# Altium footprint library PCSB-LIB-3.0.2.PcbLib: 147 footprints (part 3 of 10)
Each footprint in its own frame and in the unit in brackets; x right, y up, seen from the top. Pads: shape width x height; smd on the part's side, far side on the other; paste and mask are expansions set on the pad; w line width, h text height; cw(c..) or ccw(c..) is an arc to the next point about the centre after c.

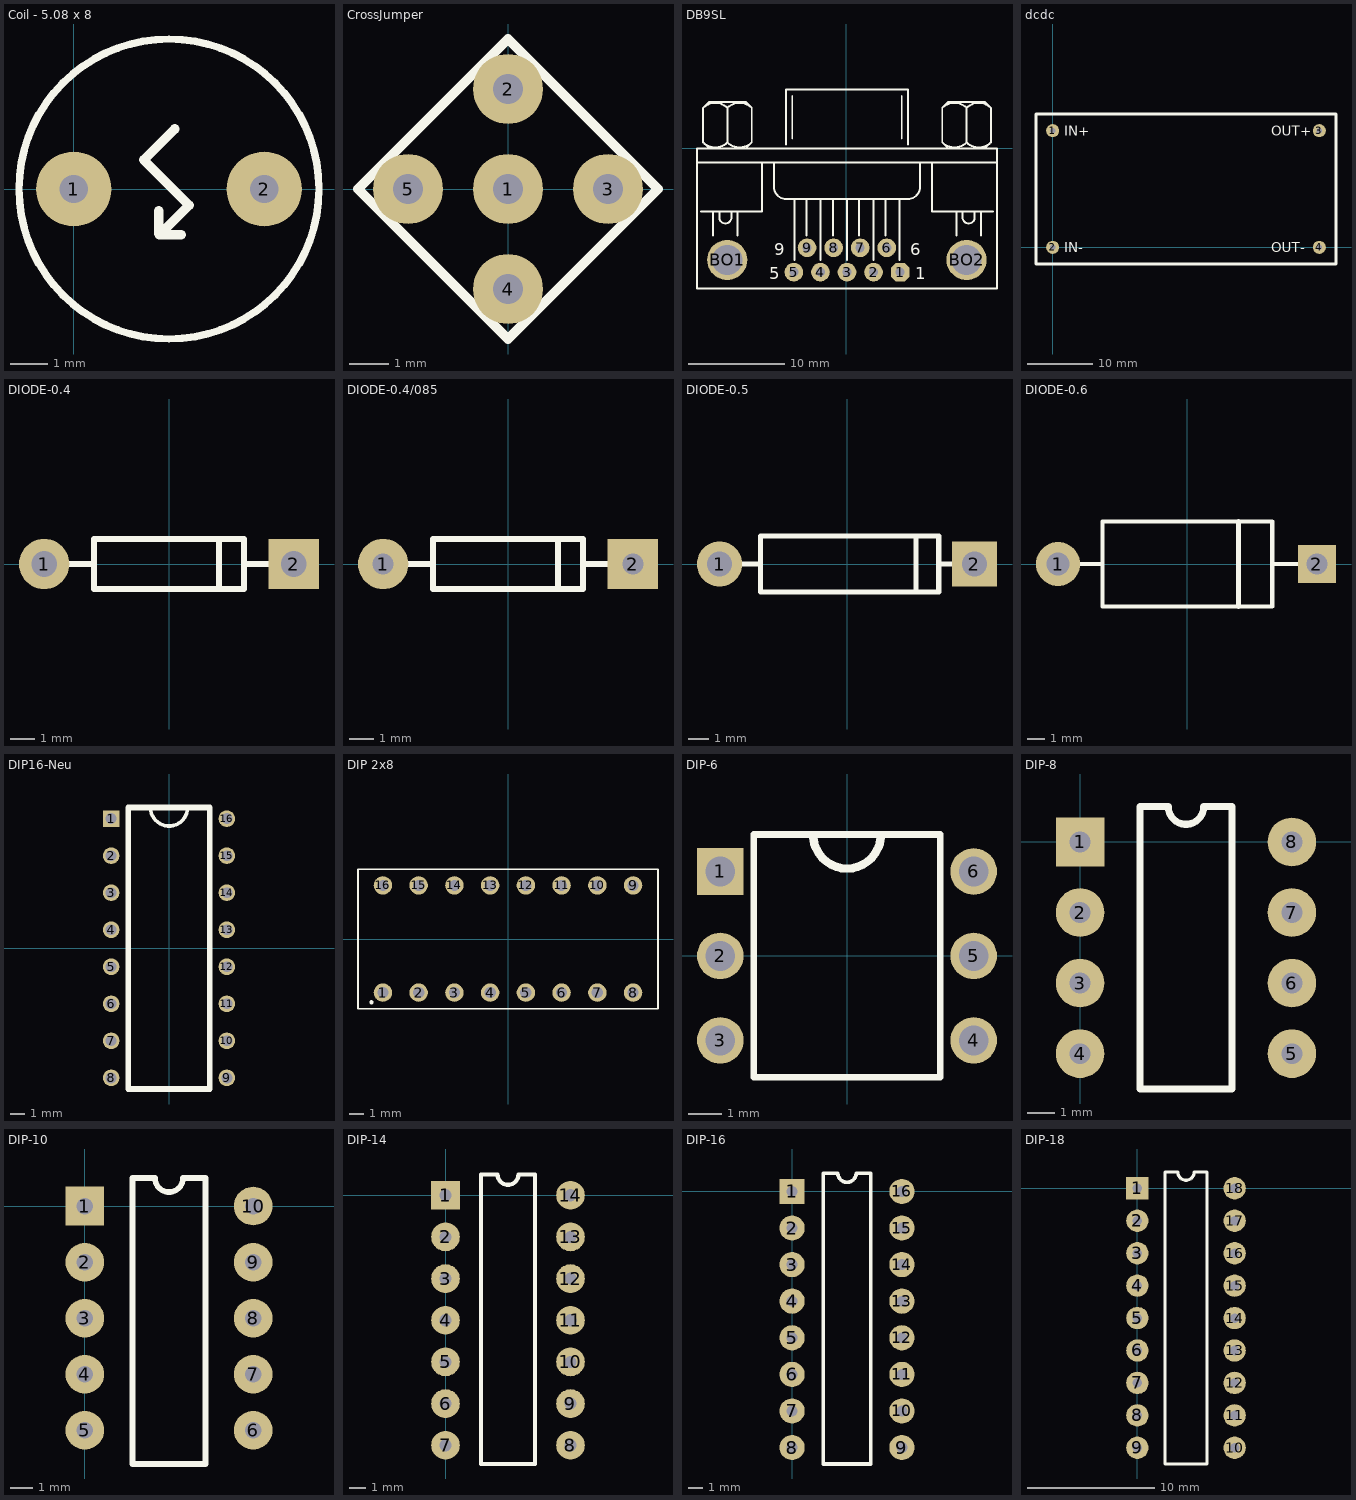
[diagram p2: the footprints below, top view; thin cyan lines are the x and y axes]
## Coil - 5.08 x 8 [mm]
pads (2):
  round 2 hole 0.75: 1(0,0) 2(5.08,0)
Top Overlay:
  circle w0.2: c2.54,0 r4
  lines w0.254: 2.261,-0.762 2.261,-1.194 ; 2.261,-0.584 2.261,-1.194 ; 2.692,1.6 1.867,0.775 3.073,-0.432 2.286,-1.219 ; 2.261,-1.194 2.286,-1.219 ; 2.286,-1.219 2.87,-1.219 ; 2.286,-1.219 2.87,-1.219 ; 2.286,-1.219 2.87,-1.219

## CrossJumper [mil]
pads (5):
  round 70 hole 30: 1(0,0) 2(0,100) 3(100,0) 4(0,-100) 5(-100,0)
Top Overlay:
  lines w10: -150,0 0,-150 150,0 0,150 -150,0

## DB9SL [mm]
pads (11):
  oct 1.95x1.95 hole 0.95: 1(5.6,-12.937)
  round 1.95 hole 0.95: 2(2.827,-12.937) 3(0.054,-12.937) 4(-2.718,-12.937) 5(-5.491,-12.937) 6(4.203,-10.397) 7(1.43,-10.397) 8(-1.343,-10.397) 9(-4.115,-10.397)
  round 4.2 hole 3.15: BO1(-12.455,-11.667) BO2(12.543,-11.667)
Top Overlay:
  lines w0.203: -15.609,-1.507 15.718,-1.507 ; -15.186,-6.587 -8.836,-6.587 -8.836,-1.507 ; -14.976,0.608 ccw(c-13.704,1.88) -12.432,0.608 ; -14.976,4.211 cw(c-13.704,2.938) -12.432,4.211 ; -14.339,-0.025 -14.974,0.61 -14.974,4.208 -14.339,4.843 -10.529,4.843 -9.894,4.208 -9.894,0.61 -10.529,-0.025 ; -13.916,-9.127 -13.916,-6.587 ; -13.281,-6.587 -13.281,-7.222 ccw(c-12.646,-7.222) -12.011,-7.222 -12.011,-6.587 ; -12.436,0.608 ccw(c-11.164,1.88) -9.892,0.608 ; -12.436,4.211 cw(c-11.164,2.938) -9.892,4.211 ; -12.434,0.61 -12.434,4.208 ; -11.376,-9.127 -11.376,-6.587 ; -7.566,-1.507 -7.566,-4.047 ccw(c-6.296,-4.047) -6.296,-5.317 6.404,-5.317 ccw(c6.404,-4.047) 7.674,-4.047 7.674,-1.507 ; -6.296,0.398 -6.296,6.113 6.404,6.113 6.404,0.398 ; -5.661,1.033 -5.661,5.478 ; -5.449,-11.667 -5.449,-5.317 ; -4.179,-9.127 -4.179,-5.317 ; -2.697,-11.667 -2.697,-5.317 ; -1.427,-9.127 -1.427,-5.317 ; 0.054,-11.667 0.054,-5.317 ; 1.324,-9.127 1.324,-5.317 ; 2.806,-11.667 2.806,-5.317 ; 4.076,-9.127 4.076,-8.915 4.076,-5.317 ; 5.558,-11.667 5.558,-5.317 ; 5.769,1.033 5.769,5.478 ; 8.944,-1.507 8.944,-6.587 15.294,-6.587 ; 10,0.608 ccw(c11.273,1.88) 12.545,0.608 ; 10,4.211 cw(c11.273,2.938) 12.545,4.211 ; 10.638,-0.025 10.003,0.61 10.003,4.208 10.638,4.843 14.448,4.843 15.083,4.208 15.083,0.61 14.448,-0.025 ; 11.484,-9.127 11.484,-6.587 ; 12.119,-6.587 12.119,-7.222 ccw(c12.754,-7.222) 13.389,-7.222 13.389,-6.587 ; 12.54,0.608 ccw(c13.813,1.88) 15.085,0.608 ; 12.54,4.211 cw(c13.813,2.938) 15.085,4.211 ; 12.543,0.61 12.543,4.208 ; 14.024,-9.127 14.024,-6.587 ; -15.609,-14.63 15.718,-14.63 15.718,-0.025 -15.609,-0.025 -15.609,-14.63
  text "6" at 6.658,-11.159 h1.27
  text "1" at 7.166,-13.699 h1.27
  text "5" at -8.074,-13.699 h1.27
  text "9" at -7.566,-11.159 h1.27

## dcdc [mm]
pads (4):
  round 2 hole 0.85: 1(0,17.78) 2(0,0) 3(40.64,17.78) 4(40.64,0)
Top Overlay:
  lines w0.4: -2.54,-2.54 -2.54,20.32 43.18,20.32 43.18,-2.54 -2.54,-2.54
  text "IN+" at 1.778,17.018 h1.52
  text "IN-" at 1.778,-0.762 h1.52
  text "OUT+" at 33.274,17.018 h1.52
  text "OUT-" at 33.274,-0.762 h1.52

## DIODE-0.4 [mm]
pads (2):
  round 2.05 hole 1.05: 1(-5.08,0)
  rect 2.05x2.05 hole 1.05: 2(5.08,0)
Top Overlay:
  lines w0.254: -4.064,0 -3.048,0 ; 2.032,-1.016 2.032,1.016 ; 3.048,0 4.064,0 ; -3.048,-1.016 3.048,-1.016 3.048,1.016 -3.048,1.016 -3.048,-1.016

## DIODE-0.4/085 [mm]
pads (2):
  round 2.05 hole 0.85: 1(-5.08,0)
  rect 2.05x2.05 hole 0.85: 2(5.08,0)
Top Overlay:
  lines w0.254: -4.064,0 -3.048,0 ; 2.032,-1.016 2.032,1.016 ; 3.048,0 4.064,0 ; -3.048,-1.016 3.048,-1.016 3.048,1.016 -3.048,1.016 -3.048,-1.016

## DIODE-0.5 [mm]
pads (2):
  round 2.25 hole 1.25: 1(-6.35,0)
  rect 2.25x2.25 hole 1.25: 2(6.35,0)
Top Overlay:
  lines w0.254: -5.334,0 -4.318,0 ; 3.429,-1.397 3.429,1.397 ; 4.699,0 5.715,0 ; -4.318,-1.397 -4.318,1.397 4.572,1.397 4.572,-1.397 -4.318,-1.397

## DIODE-0.6 [mm]
pads (2):
  round 2.6 hole 1.35: 1(-7.62,0)
  rect 2.25x2.25 hole 1.25: 2(7.62,0)
Top Overlay:
  lines w0.254: -7,0 -5,0 ; -5,-2.5 -5,2.5 5,2.5 5,-2.5 -4.89,-2.5 ; 5,0 7.016,0
  lines w0.3: 3,-2.5 3,2.5

## DIP16-Neu [mm]
pads (16):
  rect 1.14x1.14 hole 0.74: 1(-3.97,8.89)
  round 1.14 hole 0.74: 2(-3.97,6.35) 3(-3.97,3.81) 4(-3.97,1.27) 5(-3.97,-1.27) 6(-3.97,-3.81) 7(-3.97,-6.35) 8(-3.97,-8.89) 9(3.97,-8.89) 10(3.97,-6.35) 11(3.97,-3.81) 12(3.97,-1.27) 13(3.97,1.27) 14(3.97,3.81) 15(3.97,6.35) 16(3.97,8.89)
Top Overlay:
  lines w0.254: -1.253,9.443 ccw(c0,9.653) 1.27,9.652
  lines w0.4: -2.794,-9.653 -2.794,9.653 2.794,9.653 2.794,-9.653 -2.794,-9.653

## DIP 2x8 [mm]
pads (16):
  round 1.308 hole 0.8: 1(-8.89,-3.81) 2(-6.35,-3.81) 3(-3.81,-3.81) 4(-1.27,-3.81) 5(1.27,-3.81) 6(3.81,-3.81) 7(6.35,-3.81) 8(8.89,-3.81) 9(8.89,3.81) 10(6.35,3.81) 11(3.81,3.81) 12(1.27,3.81) 13(-1.27,3.81) 14(-3.81,3.81) 15(-6.35,3.81) 16(-8.89,3.81)
Top Overlay:
  circle w0.2: c-9.7,-4.5 r0.05
  lines w0.127: -10.66,-4.95 10.66,-4.95 10.66,4.95 -10.66,4.95 -10.66,-4.95

## DIP-6 [mm]
pads (6):
  rect 1.4x1.4 hole 0.9: 1(-3.81,2.54)
  round 1.4 hole 0.9: 2(-3.81,0) 3(-3.81,-2.54) 4(3.81,-2.54) 5(3.81,0) 6(3.81,2.54)
Top Overlay:
  lines w0.2: -2.8,-3.65 2.8,-3.65 2.8,3.65 1.4,3.65 -1.4,3.65 -2.8,3.65 -2.8,-3.65
  lines w0.254: -1.016,3.556 ccw(c0,3.65) 1.016,3.556

## DIP-8 [mm]
pads (8):
  rect 1.75x1.75 hole 0.75: 1(0,0)
  round 1.75 hole 0.75: 2(0,-2.54) 3(0,-5.08) 4(0,-7.62) 5(7.62,-7.62) 6(7.62,-5.08) 7(7.62,-2.54) 8(7.62,0)
Top Overlay:
  lines w0.254: 2.159,-8.89 5.461,-8.89 5.461,1.27 4.445,1.27 cw(c3.81,1.27) 3.175,1.27 2.159,1.27 2.159,-8.89

## DIP-10 [mm]
pads (10):
  rect 1.75x1.75 hole 0.75: 1(0,0)
  round 1.75 hole 0.75: 2(0,-2.54) 3(0,-5.08) 4(0,-7.62) 5(0,-10.16) 6(7.62,-10.16) 7(7.62,-7.62) 8(7.62,-5.08) 9(7.62,-2.54) 10(7.62,0)
Top Overlay:
  lines w0.254: 2.159,-11.684 2.159,1.27 3.175,1.27 ccw(c3.81,1.27) 4.445,1.27 5.461,1.27 5.461,-11.684 2.159,-11.684

## DIP-14 [mm]
pads (14):
  rect 1.75x1.75 hole 0.75: 1(0,0)
  round 1.75 hole 0.75: 2(0,-2.54) 3(0,-5.08) 4(0,-7.62) 5(0,-10.16) 6(0,-12.7) 7(0,-15.24) 8(7.62,-15.24) 9(7.62,-12.7) 10(7.62,-10.16) 11(7.62,-7.62) 12(7.62,-5.08) 13(7.62,-2.54) 14(7.62,0)
Top Overlay:
  lines w0.254: 2.159,-16.383 2.159,1.27 3.175,1.27 ccw(c3.81,1.27) 4.445,1.27 5.461,1.27 5.461,-16.383 2.159,-16.383

## DIP-16 [mm]
pads (16):
  rect 1.75x1.75 hole 0.75: 1(0,0)
  round 1.75 hole 0.75: 2(0,-2.54) 3(0,-5.08) 4(0,-7.62) 5(0,-10.16) 6(0,-12.7) 7(0,-15.24) 8(0,-17.78) 9(7.62,-17.78) 10(7.62,-15.24) 11(7.62,-12.7) 12(7.62,-10.16) 13(7.62,-7.62) 14(7.62,-5.08) 15(7.62,-2.54) 16(7.62,0)
Top Overlay:
  lines w0.254: 2.159,-18.923 5.461,-18.923 5.461,1.27 4.445,1.27 cw(c3.81,1.27) 3.175,1.27 2.159,1.27 2.159,-18.923

## DIP-18 [mm]
pads (18):
  rect 1.75x1.75 hole 0.75: 1(0,0)
  round 1.75 hole 0.75: 2(0,-2.54) 3(0,-5.08) 4(0,-7.62) 5(0,-10.16) 6(0,-12.7) 7(0,-15.24) 8(0,-17.78) 9(0,-20.32) 10(7.62,-20.32) 11(7.62,-17.78) 12(7.62,-15.24) 13(7.62,-12.7) 14(7.62,-10.16) 15(7.62,-7.62) 16(7.62,-5.08) 17(7.62,-2.54) 18(7.62,0)
Top Overlay:
  lines w0.254: 2.159,-21.59 2.159,1.27 3.175,1.27 ccw(c3.81,1.27) 4.445,1.27 5.461,1.27 5.461,-21.59 2.159,-21.59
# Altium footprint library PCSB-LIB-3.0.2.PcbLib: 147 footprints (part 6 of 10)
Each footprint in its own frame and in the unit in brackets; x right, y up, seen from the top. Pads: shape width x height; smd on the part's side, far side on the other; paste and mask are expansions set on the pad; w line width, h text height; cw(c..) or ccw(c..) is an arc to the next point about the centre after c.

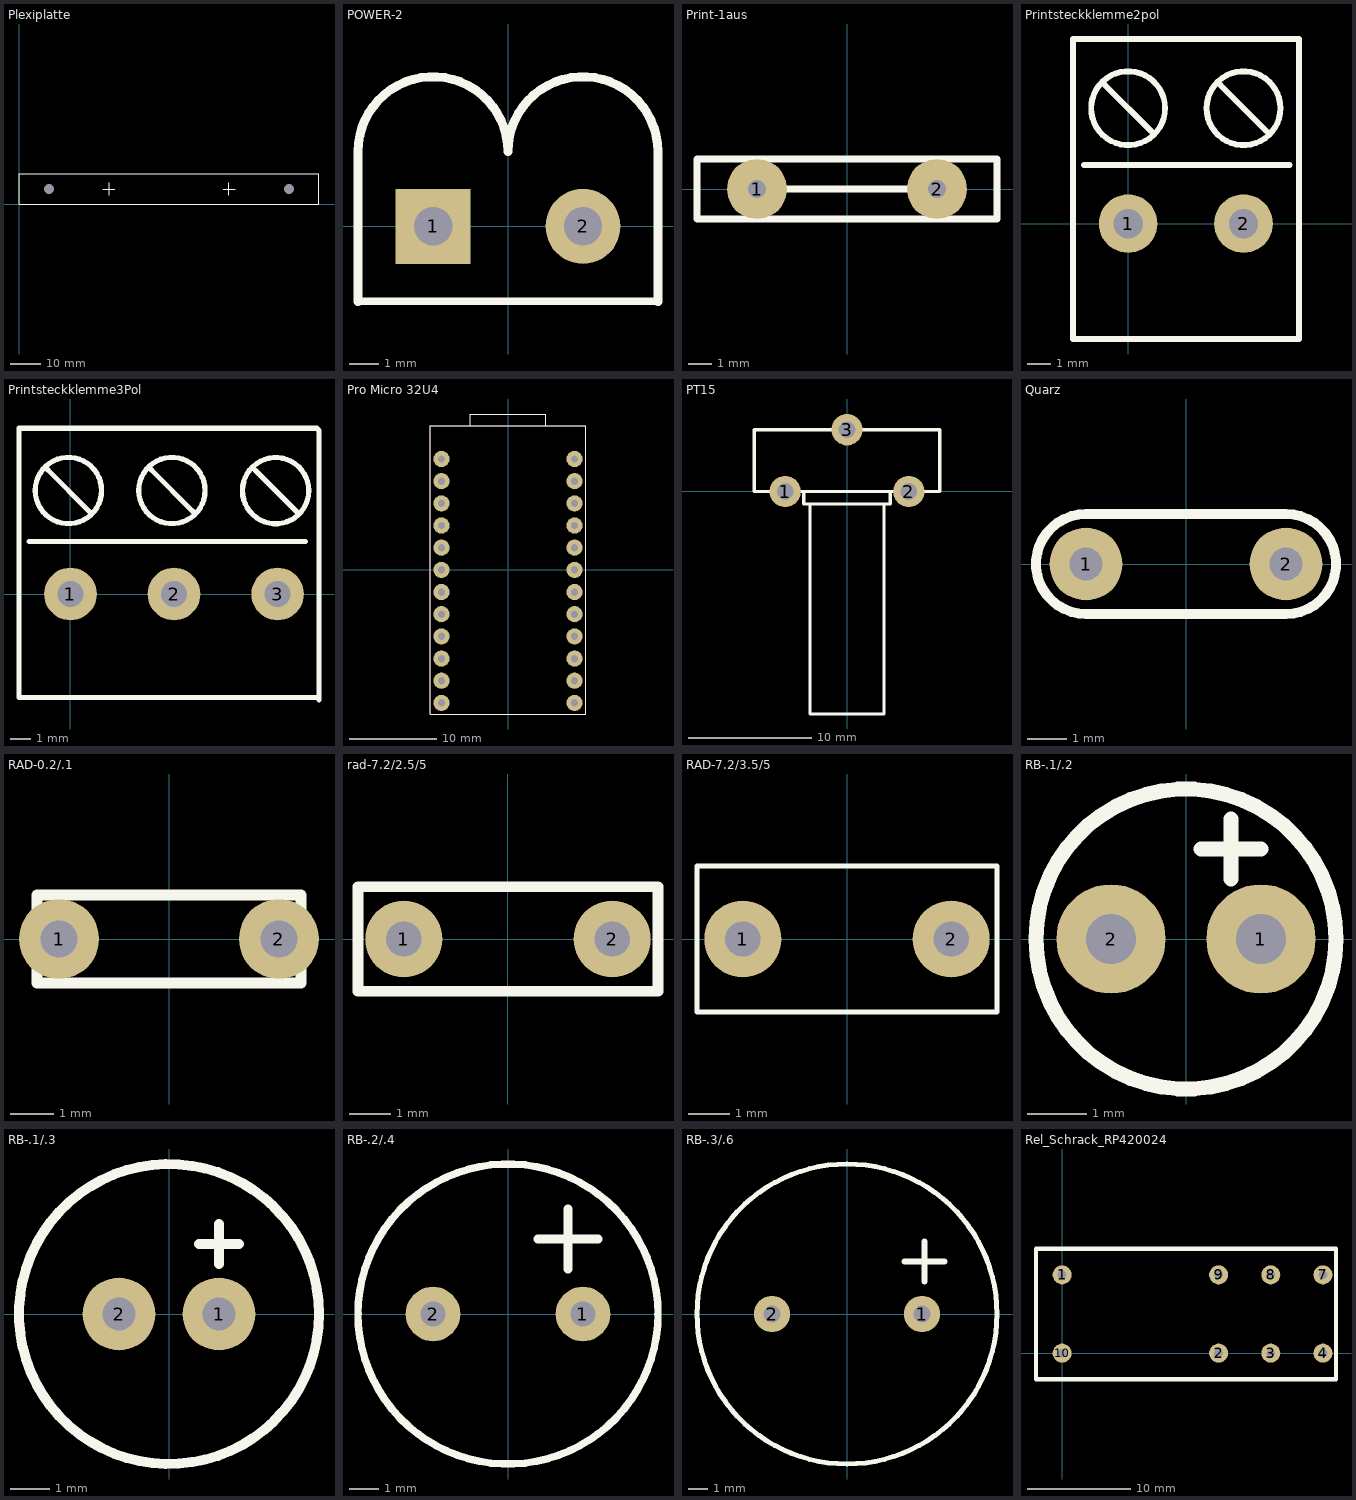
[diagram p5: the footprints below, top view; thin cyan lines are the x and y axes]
## Plexiplatte [mm]
height 60
pads (2):
  round 1.524 hole 3.2 unplated: 0(10,5) 0(90,5)
Top Overlay:
  lines w0.1: 28,5 32,5 ; 30,3 30,7 ; 68,5 72,5 ; 70,3 70,7
  lines w0.3: 0,0 100,0 100,10 0,10 0,0

## POWER-2 [mm]
pads (2):
  rect 2.54x2.54 hole 1.3: 1(-2.54,0)
  round 2.54 hole 1.3: 2(2.54,0)
Top Overlay:
  lines w0.254: -5.08,-2.54 5.08,-2.54
  lines w0.305: -5.08,-2.54 -5.085,2.531 cw(c-2.545,2.531) -0.005,2.531 cw(c2.535,2.531) 5.075,2.531 5.08,-2.54

## Print-1aus [mm]
height 8
pads (2):
  round 2.54 hole 0.75: 1(-3.81,0) 2(3.81,0)
Top Overlay:
  lines w0.3: -3.81,0 3.81,0 ; -6.35,-1.27 6.35,-1.27 6.35,1.27 0,1.27 -6.35,1.27 -6.35,-1.27

## Printsteckklemme2pol [mm] "Bestellbar bei RS Nr. 897-1297"
pads (2):
  round 2.54 hole 1.27: 1(0,0) 2(5,0)
Top Overlay:
  circle w0.254: c5,5 r1.601
  circle w0.254: c0,5 r1.601
  lines w0.1: 6,3.75 6,4
  lines w0.254: -1.905,2.54 6.985,2.54 ; -1,6 1,4 ; 4,6 6,4 ; 7.385,-5 -2.385,-5 -2.385,8 7.385,8 ; 7.4,-5 7.4,8

## Printsteckklemme3Pol [mm]
pads (3):
  round 2.54 hole 1.27: 1(0,0) 2(5,0) 3(10,0)
Top Overlay:
  circle w0.254: c9.907,4.993 r1.601
  circle w0.254: c4.9,5 r1.601
  circle w0.254: c-0.1,5 r1.601
  lines w0.1: 5.9,3.75 5.9,4 ; 10.907,3.743 10.907,3.993
  lines w0.254: -2.005,2.54 6.885,2.54 11.34,2.54 ; -1.1,6 0.9,4 ; 3.9,6 5.9,4 ; 8.907,5.993 10.907,3.993 ; 11.9,-5 7.285,-5 -2.485,-5 -2.485,8 7.285,8 11.9,8 12,7.9 12,-5.1

## Pro Micro 32U4 [mm]
pads (24):
  round 1.85 hole 0.85 mask+0.05: J3_1(-7.62,-15.24) J3_2(-7.62,-12.7) J3_3(-7.62,-10.16) J3_4(-7.62,-7.62) J3_5(-7.62,-5.08) J3_6(-7.62,-2.54) J3_7(-7.62,0) J3_8(-7.62,2.54) J3_9(-7.62,5.08) J3_10(-7.62,7.62) J3_11(-7.62,10.16) J3_12(-7.62,12.7) J4_1(7.62,12.7) J4_2(7.62,10.16) J4_3(7.62,7.62) J4_4(7.62,5.08) J4_5(7.62,2.54) J4_6(7.62,0) J4_7(7.62,-2.54) J4_8(7.62,-5.08) J4_9(7.62,-7.62) J4_10(7.62,-10.16) J4_11(7.62,-12.7) J4_12(7.62,-15.24)
Top Overlay:
  lines w0.127: -4.32,16.51 -4.32,17.855 4.32,17.855 4.32,16.51 ; -8.89,-16.51 -8.89,16.51 8.89,16.51 8.89,-16.51 -8.89,-16.51
Mechanical 13:
  lines w0.127: -8.89,-16.51 -8.89,16.51 -4.32,16.51 4.32,16.51 8.89,16.51 8.89,-16.51 -8.89,-16.51

## PT15 [mm]
pads (3):
  round 2.54 hole 1.35: 1(-5.006,-0.011) 2(4.994,-0.011) 3(-0.006,4.989)
Top Overlay:
  lines w0.254: -3.506,-0.011 -3.506,-1.011 3.494,-1.011 3.494,-0.011 ; -3,-1.011 -3,-18 3,-18 3,-1.011 ; -7.506,-0.011 -7.506,4.989 7.494,4.989 7.494,-0.011 -7.506,-0.011

## Quarz [mm]
pads (2):
  round 1.85 hole 0.85: 1(-2.54,0) 2(2.54,0)
Top Overlay:
  lines w0.254: -2.54,-1.27 cw(c-2.54,0) -2.54,1.27 2.54,1.27 cw(c2.54,0) 2.54,-1.27 -2.54,-1.27

## RAD-0.2/.1 [mm]
pads (2):
  round 1.85 hole 0.85: 1(-2.54,0) 2(2.54,0)
Top Overlay:
  lines w0.254: -3.048,-1.016 3.048,-1.016 3.048,1.016 -3.048,1.016 -3.048,-1.016

## rad-7.2/2.5/5 [mm]
pads (2):
  round 1.85 hole 0.85: 1(-2.5,0) 2(2.5,0)
Top Overlay:
  lines w0.254: -3.6,-1.25 3.6,-1.25 3.6,1.25 -3.6,1.25 -3.6,-1.25

## RAD-7.2/3.5/5 [mm]
pads (2):
  round 1.85 hole 0.85: 1(-2.5,0) 2(2.5,0)
Top Overlay:
  lines w0.127: -3.6,-1.75 3.6,-1.75 3.6,1.75 -3.6,1.75 -3.6,-1.75

## RB-.1/.2 [mm]
pads (2):
  round 1.85 hole 0.85: 1(1.27,0) 2(-1.27,0)
Top Overlay:
  circle w0.254: c0,0 r2.54
  lines w0.254: 0.254,1.524 1.27,1.524 ; 0.762,1.016 0.762,2.032

## RB-.1/.3 [mm]
pads (2):
  round 1.85 hole 0.85: 1(1.27,0) 2(-1.27,0)
Top Overlay:
  circle w0.254: c0,0 r3.81
  lines w0.254: 0.762,1.778 1.778,1.778 ; 1.27,1.27 1.27,2.286

## RB-.2/.4 [mm]
pads (2):
  round 1.85 hole 0.85: 1(2.54,0) 2(-2.54,0)
Top Overlay:
  circle w0.254: c0,0 r5.08
  lines w0.305: 1.016,2.54 3.048,2.54 ; 2.032,1.524 2.032,3.556

## RB-.3/.6 [mm]
pads (2):
  round 1.85 hole 0.85: 1(3.81,0) 2(-3.81,0)
Top Overlay:
  circle w0.254: c0,0 r7.62
  lines w0.305: 2.921,2.667 3.429,2.667 4.445,2.667 4.953,2.667 ; 3.937,1.651 3.937,2.159 3.937,3.175 3.937,3.683

## Rel_Schrack_RP420024 [mm] "24V; 2 Wechselkontakte 250V/8A"
height 25
pads (8):
  round 1.85 hole 0.85: 1(0,7.62) 2(15.24,0) 3(20.32,0) 4(25.4,0) 7(25.4,7.62) 8(20.32,7.62) 9(15.24,7.62) 10(0,0)
Top Overlay:
  lines w0.4: -2.54,-2.54 26.67,-2.54 26.67,10.16 25.4,10.16 -2.54,10.16 -2.54,-2.54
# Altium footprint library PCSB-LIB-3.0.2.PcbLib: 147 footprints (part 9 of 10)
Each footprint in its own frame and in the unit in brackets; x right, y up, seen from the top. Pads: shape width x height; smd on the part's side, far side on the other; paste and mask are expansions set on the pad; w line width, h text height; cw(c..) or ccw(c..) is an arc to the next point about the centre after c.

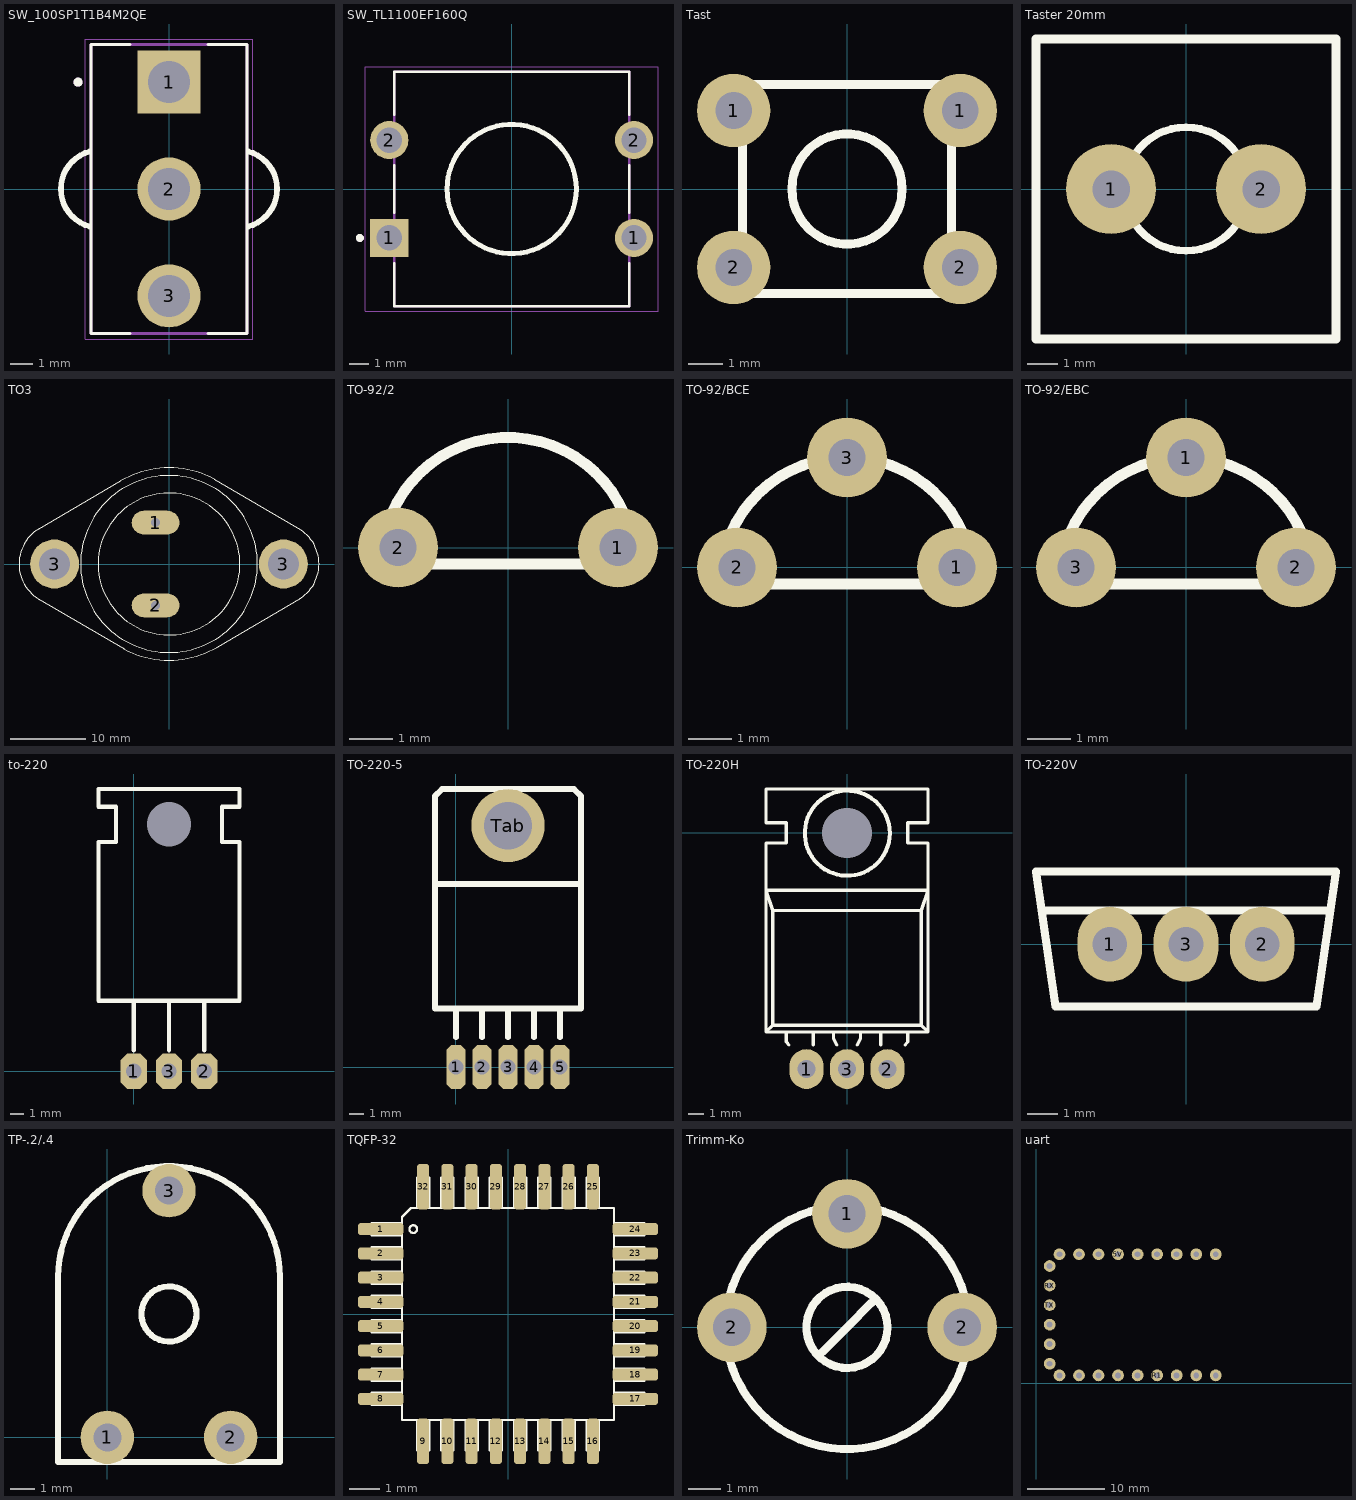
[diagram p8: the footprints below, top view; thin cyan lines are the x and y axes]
## SW_100SP1T1B4M2QE [mm]
pads (3):
  rect 2.775x2.775 hole 1.85: 1(0,4.7)
  round 2.775 hole 1.85: 2(0,0) 3(0,-4.7)
Top Overlay:
  circle w0.2: c-4,4.7 r0.1
  lines w0.127: -1.71,-6.35 -3.43,-6.35 -3.43,6.35 -1.71,6.35 ; 1.71,-6.35 3.43,-6.35 3.43,6.35 1.71,6.35
  lines w0.254: -3.49,-1.65 cw(c-3.048,0) -3.49,1.65 ; 3.49,-1.65 ccw(c3.048,0) 3.49,1.65
Mechanical 13:
  circle w0.2: c-4,4.7 r0.1
  lines w0.127: -3.43,-6.35 -3.43,6.35 3.43,6.35 3.43,-6.35 -3.43,-6.35
Mechanical 15:
  lines w0.05: -3.68,-6.6 -3.68,6.6 3.68,6.6 3.68,-6.6 -3.68,-6.6

## SW_TL1100EF160Q [mm]
height 7.8
pads (4):
  rect 1.95x1.95 hole 1.3: 1(-6.25,-2.5)
  round 1.95 hole 1.3: 1(6.25,-2.5) 2(-6.25,2.5) 2(6.25,2.5)
Top Overlay:
  circle w0.2: c-7.75,-2.5 r0.1
  circle w0.254: c0,0 r3.302
  lines w0.127: -6,-3.788 -6,-6 6,-6 6,-3.788 ; -6,-1.212 -6,1.212 ; -6,3.788 -6,6 6,6 6,3.788 ; 6,-1.212 6,1.212
Mechanical 13:
  circle w0.2: c-7.75,-2.5 r0.1
  lines w0.127: -6,-6 -6,6 6,6 6,-6 -6,-6
Mechanical 15:
  lines w0.05: -7.475,-6.25 7.475,-6.25 7.475,6.25 -7.475,6.25 -7.475,-6.25

## Tast [mm]
pads (4):
  round 2.1 hole 1.05: 1(-3.25,2.25) 1(3.25,2.25) 2(-3.25,-2.25) 2(3.25,-2.25)
Top Overlay:
  circle w0.254: c0,0 r1.581
  lines w0.254: -3,-3 -3,3 3,3 3,-3 -3,-3

## Taster 20mm [mm]
height 20
pads (2):
  round 3 hole 1.25 unplated: 1(-2.5,0) 2(2.5,0)
Top Overlay:
  circle w0.254: c0,0 r2.062
  lines w0.3: -5,-5 -5,5 5,5 5,-5 -5,-5

## TO3 [mil]
pads (4):
  oval 248x124 hole 47.05: 1(-70,215) 2(-70,-215)
  round 255 hole 162: 3(-595,0) 3(595,0)
Top Overlay:
  circle w6: c0,0 r369
  circle w2: c0,0 r460
  lines w6: -680,180 -250,433 cw(c0,0) 0,500 cw(c0,0) 234.74,441.47 ; -679,-181 -234,-442 ; -676.7,-182.58 cw(c-567,0) -780,0 cw(c-567,0) -673.5,184.46 ; -234.74,-441.47 ccw(c0,0) 0,-500 ccw(c0,0) 250,-433.01 ; 235,441 684,178 ; 251,-433 684,-178 ; 683.01,-178.64 ccw(c567,0) 780,0 ccw(c567,0) 683.01,178.64
Mechanical 13:
  circle w6: c595,0 r85
  circle w6: c-595,0 r85

## TO-92/2 [mm]
pads (2):
  round 1.85 hole 0.85: 1(2.54,0) 2(-2.54,0)
Top Overlay:
  lines w0.254: -2.927,-0.381 cw(c-0.003,-0.381) 2.921,-0.381 -2.927,-0.381

## TO-92/BCE [mm]
pads (3):
  round 1.85 hole 0.85: 1(2.54,0) 2(-2.54,0) 3(0,2.54)
Top Overlay:
  lines w0.254: -2.927,-0.381 cw(c-0.003,-0.381) 2.921,-0.381 -2.927,-0.381

## TO-92/EBC [mm] "Standard-Transistor wie BC546"
pads (3):
  round 1.85 hole 0.85: 1(0,2.54) 2(2.54,0) 3(-2.54,0)
Top Overlay:
  lines w0.254: -2.927,-0.381 cw(c-0.003,-0.381) 2.921,-0.381 -2.927,-0.381

## to-220 [mm]
pads (4):
  round 0 hole 3.2 unplated: 0(2.537,17.788)
  oct 1.905x2.54 hole 1.1: 1(-0.003,0.008) 2(5.077,0.008) 3(2.537,0.008)
Top Overlay:
  lines w0.305: -0.003,1.532 -0.003,5.088 ; 2.537,1.532 2.537,5.088 ; 5.077,1.532 5.077,5.088 ; -2.543,5.088 7.617,5.088 7.617,16.518 6.347,16.518 6.347,19.058 7.617,19.058 7.617,20.328 -2.543,20.328 -2.543,19.058 -1.273,19.058 -1.273,16.518 -2.543,16.518 -2.543,5.088

## TO-220-5 [mm]
height 5
pads (6):
  oct 1.3x3 hole 1.05: 1(0,0) 2(1.778,0) 3(3.556,0) 4(5.334,0) 5(7.112,0)
  round 5 hole 3.25: Tab(3.556,16.5)
Top Overlay:
  lines w0.4: 0,2.032 0,4 ; 1.778,2.032 1.778,4 ; 3.556,2.032 3.556,4 ; 3.556,16.5 3.556,19 ; 5.334,2.032 5.334,4 ; 7.112,2.032 7.112,4 ; -1.444,12.5 -1.444,18.5 -0.944,19 8.056,19 8.556,18.5 ; -1.444,12.5 -1.444,4 8.556,4 8.556,12.5 ; -1.444,12.5 8.556,12.5 ; 8.556,12.5 8.556,18.5 ; 8.556,18.5 8.556,18.5

## TO-220H [mm]
pads (4):
  round 0 hole 3.15: 0(0,0)
  oval 2.15x2.5 hole 1.15: 1(-2.54,-14.817) 2(2.54,-14.817) 3(0,-14.817)
Top Overlay:
  circle w0.254: c0.017,-0.02 r2.667
  lines w0.2: -3.81,-13.123 -3.81,-12.488 ; -3.762,-13.155 -3.647,-13.317 ; -2.117,-13.317 -2.117,-12.488 ; -0.847,-12.488 -0.847,-12.912 -0.635,-13.317 ; 0.635,-13.317 0.847,-12.912 0.847,-12.488 ; 2.117,-13.317 2.117,-12.488 ; 3.655,-13.317 3.818,-13.099 ; 3.81,-13.123 3.81,-12.488 ; -5.08,-12.488 -4.657,-12.065 ; -5.08,-12.488 5.08,-12.488 ; -5.08,-12.488 -5.08,-0.635 -3.81,-0.635 -3.81,0.635 -5.08,0.635 -5.08,2.752 5.08,2.752 5.08,0.635 3.81,0.635 3.81,-0.635 5.08,-0.635 5.08,-12.488 ; -4.657,-12.065 4.657,-12.065 ; -4.657,-12.065 -4.657,-4.868 ; -4.657,-4.868 4.657,-4.868 ; -4.657,-4.868 -5.08,-3.598 5.08,-3.598 4.657,-4.868 ; 4.657,-12.065 5.08,-12.488 ; 4.657,-12.065 4.657,-4.868

## TO-220V [mm]
pads (3):
  oval 2.15x2.5 hole 1.15: 1(-2.54,0) 2(2.54,0) 3(0,0)
Top Overlay:
  lines w0.254: -4.812,1.125 4.808,1.125 ; -5,2.425 -4.35,-2.075 0,-2.075 4.35,-2.075 5,2.425 0,2.425 -5,2.425

## TP-.2/.4 [mm] "Trimpotentiometer liegend klein"
pads (3):
  round 2.2 hole 1.15: 1(0,0) 2(5.08,0) 3(2.54,10.16)
Top Overlay:
  circle w0.254: c2.54,5.08 r1.136
  lines w0.254: -2.032,-1.016 7.112,-1.016 7.112,6.604 ccw(c2.54,6.604) -2.032,6.604 -2.032,-1.016

## TQFP-32 [mm]
height 1.2
pads (32):
  rrect50% 1.5x0.4 smd: 1(-4.2,2.8) 2(-4.2,2) 3(-4.2,1.2) 4(-4.2,0.4) 5(-4.2,-0.4) 6(-4.2,-1.2) 7(-4.2,-2) 8(-4.2,-2.8) 17(4.2,-2.8) 18(4.2,-2) 19(4.2,-1.2) 20(4.2,-0.4) 21(4.2,0.4) 22(4.2,1.2) 23(4.2,2) 24(4.2,2.8)
  rrect50% 0.4x1.5 smd: 9(-2.8,-4.2) 10(-2,-4.2) 11(-1.2,-4.2) 12(-0.4,-4.2) 13(0.4,-4.2) 14(1.2,-4.2) 15(2,-4.2) 16(2.8,-4.2) 25(2.8,4.2) 26(2,4.2) 27(1.2,4.2) 28(0.4,4.2) 29(-0.4,4.2) 30(-1.2,4.2) 31(-2,4.2) 32(-2.8,4.2)
Top Overlay:
  circle w0.076: c-3.127,2.8 r0.127
  lines w0.076: -3.5,-3 -4.5,-3 -4.5,-2.6 -3.5,-2.6 ; -3.5,-2.2 -4.5,-2.2 ; -3.5,-1.8 -4.5,-1.8 ; -3.5,-1.4 -4.5,-1.4 ; -3.5,-1 -4.5,-1 ; -3.5,-0.6 -4.5,-0.6 ; -3.5,-0.2 -4.5,-0.2 ; -3.5,0.2 -4.5,0.2 ; -3.5,0.6 -4.5,0.6 ; -3.5,1 -4.5,1 ; -3.5,1.4 -4.5,1.4 ; -3.5,1.8 -4.5,1.8 ; -3.5,2.2 -4.5,2.2 ; -3.5,2.6 -4.5,2.6 ; -3.5,3 -4.5,3 ; -3,-3.5 -3,-4.5 -2.6,-4.5 -2.6,-3.5 ; -3,3.5 -3,4.5 -2.6,4.5 -2.6,3.5 ; -2.2,-3.5 -2.2,-4.5 ; -2.2,3.5 -2.2,4.5 ; -1.8,-3.5 -1.8,-4.5 ; -1.8,3.5 -1.8,4.5 ; -1.4,-3.5 -1.4,-4.5 ; -1.4,3.5 -1.4,4.5 ; -1,-3.5 -1,-4.5 ; -1,3.5 -1,4.5 ; -0.6,-3.5 -0.6,-4.5 ; -0.6,3.5 -0.6,4.5 ; 0.2,-3.5 0.2,-4.5 ; 0.2,3.5 0.2,4.5 ; 0.6,-3.5 0.6,-4.5 ; 0.6,3.5 0.6,4.5 ; 1,-3.5 1,-4.5 ; 1,3.5 1,4.5 ; 1.4,-3.5 1.4,-4.5 ; 1.4,3.5 1.4,4.5 ; 1.8,-3.5 1.8,-4.5 2.2,-4.5 2.2,-3.5 ; 1.8,3.5 1.8,4.5 ; 2.2,3.5 2.2,4.5 ; 2.6,-3.5 2.6,-4.5 3,-4.5 3,-3.5 ; 2.6,3.5 2.6,4.5 3,4.5 3,3.5 ; 3.5,-3 4.5,-3 ; 3.5,-2.6 4.5,-2.6 ; 3.5,-2.2 4.5,-2.2 ; 3.5,-1.8 4.5,-1.8 ; 3.5,-1.4 4.5,-1.4 ; 3.5,-1 4.5,-1 ; 3.5,-0.6 4.5,-0.6 ; 3.5,-0.2 4.5,-0.2 ; 3.5,0.2 4.5,0.2 ; 3.5,0.6 4.5,0.6 ; 3.5,1 4.5,1 ; 3.5,1.4 4.5,1.4 ; 3.5,1.8 4.5,1.8 ; 3.5,2.2 4.5,2.2 ; 3.5,2.6 4.5,2.6 4.5,3 3.5,3 ; -4.5,-2.2 -4.5,-1.8 ; -4.5,-2.2 -4.5,-1.8 ; -4.5,-1.4 -4.5,-1 ; -4.5,-1.4 -4.5,-1 ; -4.5,-0.6 -4.5,-0.2 ; -4.5,-0.6 -4.5,-0.2 ; -4.5,0.2 -4.5,0.6 ; -4.5,0.2 -4.5,0.6 ; -4.5,1 -4.5,1.4 ; -4.5,1 -4.5,1.4 ; -4.5,1.8 -4.5,2.2 ; -4.5,1.8 -4.5,2.2 ; -4.5,2.6 -4.5,3 ; -4.5,2.6 -4.5,3 ; -3.5,3.2 -3.5,-3.5 3.5,-3.5 3.5,3.5 -3.2,3.5 ; -3.5,3.2 -3.5,3.2 ; -3.5,3.2 -3.2,3.5 ; -3.5,3.2 -3.2,3.5 ; -2.2,-4.5 -1.8,-4.5 ; -2.2,-4.5 -1.8,-4.5 ; -2.2,4.5 -1.8,4.5 ; -2.2,4.5 -1.8,4.5 ; -1.4,-4.5 -1,-4.5 ; -1.4,-4.5 -1,-4.5 ; -1.4,4.5 -1,4.5 ; -1.4,4.5 -1,4.5 ; -0.6,-4.5 -0.2,-4.5 ; -0.6,-4.5 -0.2,-4.5 ; -0.6,4.5 -0.2,4.5 ; -0.6,4.5 -0.2,4.5 ; -0.2,-4.5 -0.2,-3.5 -0.2,-4.5 ; -0.2,4.5 -0.2,3.5 -0.2,4.5 ; 0.2,-4.5 0.6,-4.5 ; 0.2,-4.5 0.6,-4.5 ; 0.2,4.5 0.6,4.5 ; 0.2,4.5 0.6,4.5 ; 1,-4.5 1.4,-4.5 ; 1,-4.5 1.4,-4.5 ; 1,4.5 1.4,4.5 ; 1,4.5 1.4,4.5 ; 1.8,4.5 2.2,4.5 ; 1.8,4.5 2.2,4.5 ; 4.5,-3 4.5,-2.6 ; 4.5,-3 4.5,-2.6 ; 4.5,-2.2 4.5,-1.8 ; 4.5,-2.2 4.5,-1.8 ; 4.5,-1.4 4.5,-1 ; 4.5,-1.4 4.5,-1 ; 4.5,-0.6 4.5,-0.2 ; 4.5,-0.6 4.5,-0.2 ; 4.5,0.2 4.5,0.6 ; 4.5,0.2 4.5,0.6 ; 4.5,1 4.5,1.4 ; 4.5,1 4.5,1.4 ; 4.5,1.8 4.5,2.2 ; 4.5,1.8 4.5,2.2

## Trimm-Ko [mm]
pads (3):
  round 2.15 hole 1.15: 1(0,3.5) 2(-3.55,0) 2(3.55,0)
Top Overlay:
  circle w0.254: c0,0 r1.25
  circle w0.254: c0,0 r3.75
  lines w0.254: -0.762,-0.762 0,0 0.762,0.762

## uart [mil]
pads (24):
  round 60 hole 30: 3V3(520,660) 5V(420,660) CTS(70,200) CTS(620,660) DCD(920,40) DTR(70,600) DTR(220,40) ENTEN(820,660) GND(70,100) GND(120,660) GND(720,40) PWR(920,660) R1(620,40) RSD(820,40) RTS(320,40) RX(70,500) RXC(520,40) RXL(320,660) SLEEP(720,660) TX(70,400) TXD(120,40) TXL(220,660) VCC(70,300) VCC(420,40)
Bottom Overlay:
  lines w10: 0,0 0,708.66 1417.32,708.66 1417.32,0 0,0 ; 1259.84,196.85 1535.43,196.85 1535.43,511.81 1338.58,511.81 1259.84,511.81 1259.84,196.85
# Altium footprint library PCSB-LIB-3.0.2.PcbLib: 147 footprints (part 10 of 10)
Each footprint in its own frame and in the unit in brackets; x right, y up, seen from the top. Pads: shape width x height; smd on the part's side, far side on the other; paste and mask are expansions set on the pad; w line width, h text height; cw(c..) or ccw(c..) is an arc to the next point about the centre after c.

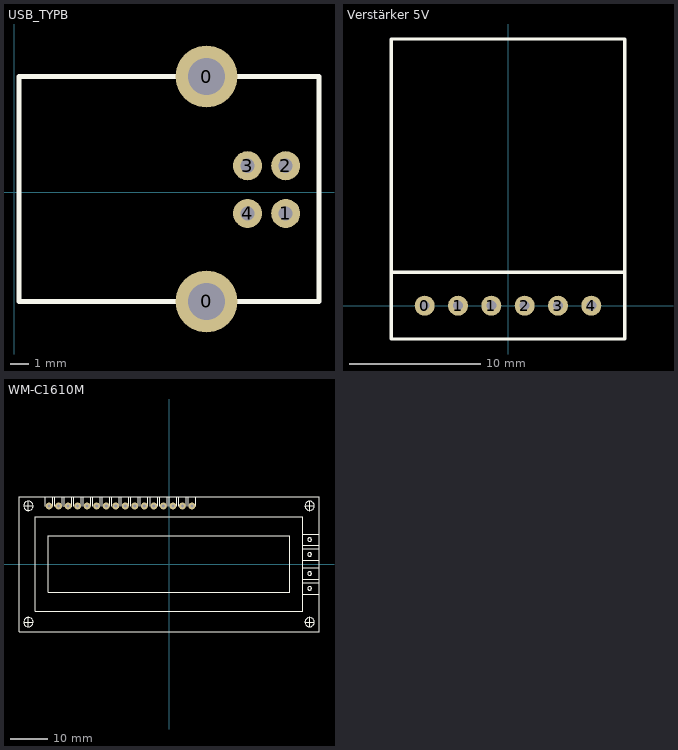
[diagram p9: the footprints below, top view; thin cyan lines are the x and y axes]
## USB_TYPB [mm]
pads (6):
  round 3.3 hole 1.95: 0(10.251,-5.833) 0(10.251,6.167)
  round 1.55 hole 0.75: 1(14.475,-1.134) 2(14.475,1.406) 3(12.443,1.406) 4(12.443,-1.134)
Top Overlay:
  lines w0.254: 16.251,6.107 16.251,-5.833 0.251,-5.833 0.251,6.167 16.251,6.167

## Verstärker 5V [mil]
pads (6):
  round 60 hole 30: 0(-250,0) 1(-150,0) 1(-50,0) 2(50,0) 3(150,0) 4(250,0)
Top Overlay:
  lines w10: -350,100 350,100 ; -350,-100 350,-100 350,800 -350,800 -350,0 -350,-100

## WM-C1610M [mm]
pads (16):
  round 1.85 hole 0.85: 1(-32,15.5) 2(-29.46,15.5) 3(-26.92,15.5) 4(-24.38,15.5) 5(-21.84,15.5) 6(-19.3,15.5) 7(-16.76,15.5) 8(-14.22,15.5) 9(-11.68,15.5) 10(-9.14,15.5) 11(-6.6,15.5) 12(-4.06,15.5) 13(-1.52,15.5) 14(1.02,15.5) 15(3.56,15.5) 16(6.1,15.5)
Top Overlay:
  circle w0.2: c-37.51,15.538 r1.25
  circle w0.2: c-37.51,-15.462 r1.25
  circle w0.2: c37.49,15.538 r1.25
  circle w0.2: c37.49,6.538 r0.5
  circle w0.2: c37.49,2.578 r0.5
  circle w0.2: c37.49,-2.502 r0.5
  circle w0.2: c37.49,-6.462 r0.5
  circle w0.2: c37.49,-15.462 r1.25
  lines w0.1: -38.75,-15.462 -36.26,-15.462 ; -38.75,15.538 -36.26,15.538 ; -37.51,-16.75 -37.51,-14.25 ; -37.51,14.25 -37.51,16.75 ; 36.25,-15.462 38.74,-15.462 ; 36.25,15.538 38.74,15.538 ; 37.49,-16.75 37.49,-14.25 ; 37.49,14.25 37.49,16.75
  lines w0.2: -33.01,15.498 -33.01,18.038 ; -31.01,15.498 -31.01,18.038 ; -30.47,15.498 -30.47,18.038 ; -28.47,15.498 -28.47,18.038 ; -27.93,15.338 -27.93,18.038 ; -25.93,15.338 -25.93,18.038 ; -25.39,15.498 -25.39,18.038 ; -23.39,15.498 -23.39,18.038 ; -22.85,15.498 -22.85,18.038 ; -20.85,15.498 -20.85,18.038 ; -20.31,15.498 -20.31,18.038 ; -18.31,15.498 -18.31,18.038 ; -17.77,15.498 -17.77,18.038 ; -15.77,15.498 -15.77,18.038 ; -15.23,15.498 -15.23,18.038 ; -13.23,15.498 -13.23,18.038 ; -12.69,15.498 -12.69,18.038 ; -10.69,15.498 -10.69,18.038 ; -10.15,15.468 -10.15,18.038 ; -8.15,15.468 -8.15,18.038 ; -7.61,15.468 -7.61,18.038 ; -5.61,15.468 -5.61,18.038 ; -5.07,15.498 -5.07,18.038 ; -3.07,15.498 -3.07,18.038 ; -2.53,15.498 -2.53,18.038 ; -0.53,15.498 -0.53,18.038 ; 0.01,15.498 0.01,18.038 ; 2.01,15.498 2.01,18.038 ; 2.55,15.498 2.55,18.038 ; 4.55,15.498 4.55,18.038 ; 5.09,15.498 5.09,18.038 ; 7.09,15.498 7.09,18.038 ; 35.59,-7.962 39.99,-7.962 ; 35.59,-4.962 39.99,-4.962 ; 35.59,-4.002 39.99,-4.002 ; 35.59,-1.002 39.99,-1.002 ; 35.59,1.078 39.99,1.078 ; 35.59,4.078 39.99,4.078 ; 35.59,5.038 39.99,5.038 ; 35.59,8.038 39.99,8.038 ; -40.01,-17.962 39.99,-17.962 39.99,18.038 -40.01,18.038 -40.01,-17.962 ; -35.61,-12.562 -35.61,12.638 35.59,12.638 35.59,-12.562 -35.61,-12.562 ; -32.24,-7.462 32.22,-7.462 32.22,7.538 -32.24,7.538 -32.24,-7.462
